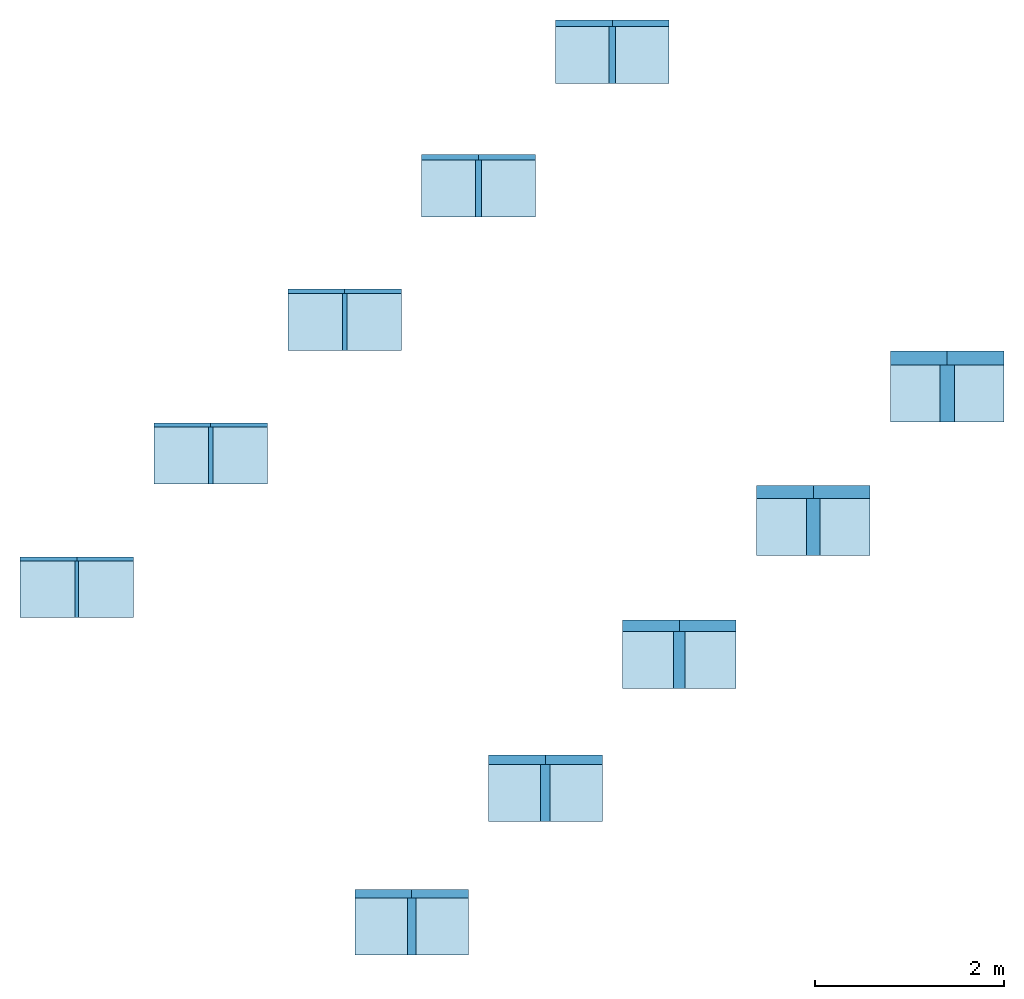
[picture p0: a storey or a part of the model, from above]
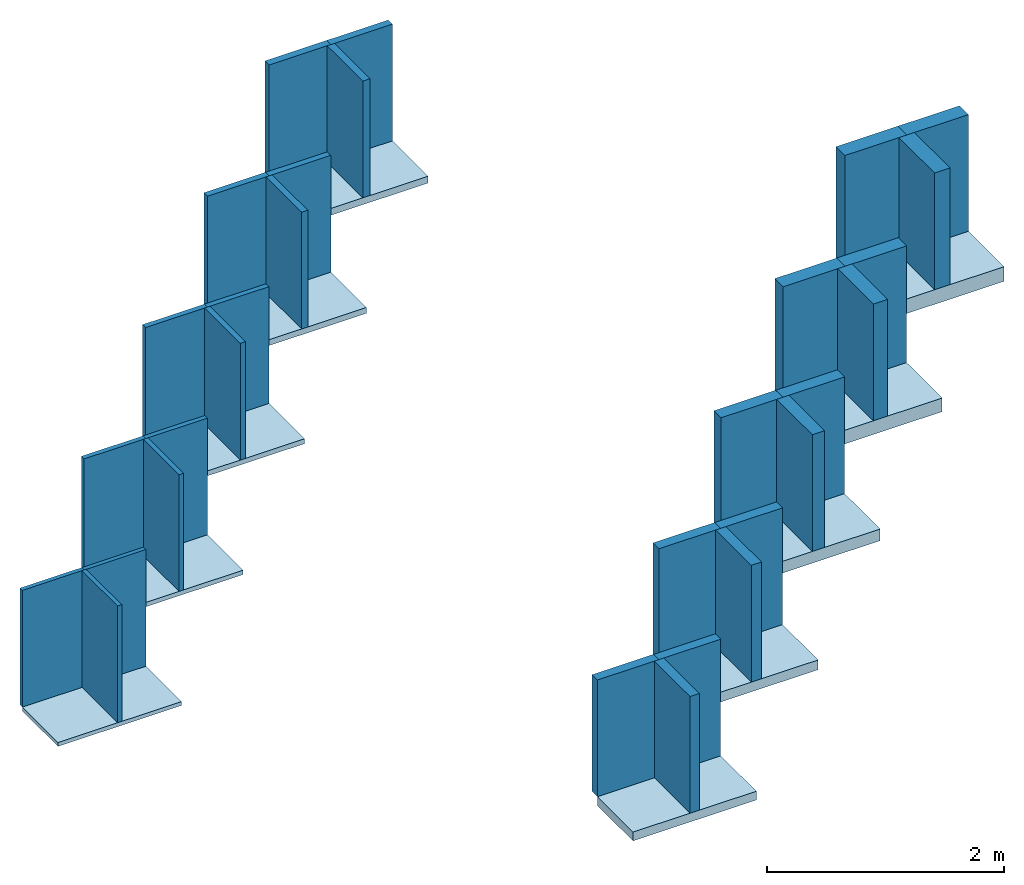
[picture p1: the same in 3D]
Properties of the parts of a building model (IFC2X3)

# File
Description: ViewDefinition [CoordinationView_V2.0, QuantityTakeOffAddOnView]
Time: 2021-05-19T20:16:55
Written by: The EXPRESS Data Manager Version 5.02.0100.07 : 28 Aug 2013
Made in: 20190108_1515(x64) - Exporter 19.1.0.0 - Alternate UI 19.1.0.0
Comment: STEP Physical File produced by: The EXPRESS Data Manager Version 5.02.0100.07 : 28 Aug 2013 * Module: EDMstepFileFactory/EDMstandAlone * Creation date: Wed May 19 20:16:55 2021 * Host: lt-026 * Database: C:\Users\WF2BF~1.POE\AppData\Local\Temp\{A69A01DA-EC1D-4794-8E67-495A6B97D631}\ifc * Database version: 5507 * Database creation date: Wed May 19 20:16:54 2021 * Schema: IFC2X3 * Model: DataRepository.ifc * Model creation date: Wed May 19 20:16:54 2021 * Header model: DataRepository.ifc_HeaderModel * Header model creation date: Wed May 19 20:16:54 2021 * EDMuser: sdai-user * EDMgroup: sdai-group * License ID and type: 5605 : Permanent license. Expiry date: * EDMstepFileFactory options: 020000

# IfcSite, Default
RefLatitude: 42, 24, 53, 508911; RefLongitude: -71, -15, -29, -58837; RefElevation: 0 mm
Other - Category: Project Information

# IfcBuilding
Pset_BuildingCommon - NumberOfStoreys: 1
Pset_ProductRequirements - Category: Project Information; sets with these values: 2

# IfcBuildingStorey: Level:Level 1, begane grond
LongName: begane grond; Elevation: 0 mm
Pset_AirSideSystemInformation - Name: begane grond
Pset_ProductRequirements - Name: begane grond; Category: Levels
Constraints - Elevation: 0 mm
Dimensions - Computation Height: 0 mm
Identity Data - Structural: no; Building Story: yes; Name: begane grond
Other - Category: Levels; Family: Level: Level 1; Family and Type: Level: Level 1; Type: Level: Level 1; Type Id: Level: Level 1
Constraints(Type) - Elevation Base: Project Base Point
Graphics(Type) - Color: 0; Line Pattern: Solid; Line Weight: 1; Symbol: NLRS_00_LAB_niveau bovenkant_gen_cadix: 1.8mm; Symbol at End 1 Default: no; Symbol at End 2 Default: yes
Identity Data(Type) - Type Name: Level 1
Other(Type) - Category: Levels; Family Name: Level

# IfcSlab: Floor:NLRS_23_FL_Mineral Wool_100x600x1200mm, Floor:NLRS_23_FL_Mineral Wool_100x600x1200mm:5011
In: begane grond
Type - PredefinedType: FLOOR; Material: Knauf Insulation_Mineral Wool 35 Ecose®minerale wol 100 mm
Type - Analytical Properties - Roughness: 1; Thermal mass: 0; Absorptance: 0.1; Heat Transfer Coefficient (U): 0.35; Thermal Resistance (R): 2.85714
Type - Construction - Function: Interior; Default Thickness: 100 mm
Type - Graphics - Coarse Scale Fill Color: 0
Type - Identity Data - Type Image: Raster image: MW 35 .jpg (2); Assembly Code: 23; Assembly Description: Vloeren; Description: Mineral Wool 35 - 100mm; Manufacturer: Knauf Insulation B.V.; Model: Mineral Wool 35 is een onbeklede minerale wolplaat met ECOSE® Technology.; Type Name: NLRS_23_FL_Mineral Wool_100x600x1200mm; URL: www.knaufinsulation.nl
Type - Other - Category: Floors; Family Name: Floor
Type - Pset_ElementShading - Roughness: 304.8 mm
Type - Pset_ManufacturerTypeInformation - Manufacturer: Knauf Insulation B.V.
Type - Pset_ProductRequirements - Category: Floors
Type - Pset_QuantityTakeOff - Reference: NLRS_23_FL_Mineral Wool_100x600x1200mm
Type - Pset_ReinforcementBarPitchOfSlab - Description: Mineral Wool 35 - 100mm; Reference: NLRS_23_FL_Mineral Wool_100x600x1200mm
Type - Pset_SlabCommon - IsExternal: no; ThermalTransmittance: 0.35 kg/K/s3; Reference: NLRS_23_FL_Mineral Wool_100x600x1200mm
Classification: 23 Vloeren (Uniformat)
Pset_SlabCommon - LoadBearing: no; PitchAngle: 0 deg
BaseQuantities - GrossArea: 0.72 m2; NetArea: 1.8 m2; GrossVolume: 72 m3; NetVolume: 0.072 m3; Perimeter: 3600 mm; Width: 100 mm
Constraints - Related to Mass: no; Room Bounding: yes; Height Offset From Level: 0 mm; Level: Level: begane grond
Dimensions - Elevation at Top: 0 mm; Area: 0.72 m2; Elevation at Bottom: -100 mm; Perimeter: 3600 mm; Thickness: 100 mm; Volume: 0.072 m3
Other - Family: Floor: NLRS_23_FL_Mineral Wool_100x600x1200mm; Family and Type: Floor: NLRS_23_FL_Mineral Wool_100x600x1200mm; Type: Floor: NLRS_23_FL_Mineral Wool_100x600x1200mm; Type Id: Floor: NLRS_23_FL_Mineral Wool_100x600x1200mm
Phasing - Phase Created: New Construction
Structural - Enable Analytical Model: no; Structural: no

# IfcSlab: Floor:NLRS_23_FL_Mineral Wool_120x600x1200mm, Floor:NLRS_23_FL_Mineral Wool_120x600x1200mm:5060
In: begane grond
Type - PredefinedType: FLOOR; Material: Knauf Insulation_Mineral Wool 35 Ecose®minerale wol 120 mm
Type - Analytical Properties - Roughness: 1; Thermal mass: 0; Absorptance: 0.1; Heat Transfer Coefficient (U): 0.291667; Thermal Resistance (R): 3.42857
Type - Construction - Function: Interior; Default Thickness: 120 mm
Type - Graphics - Coarse Scale Fill Color: 0
Type - Identity Data - Type Image: Raster image: MW 35 .jpg (2); Assembly Code: 23; Assembly Description: Vloeren; Description: Mineral Wool 35 - 120mm; Manufacturer: Knauf Insulation B.V.; Model: Mineral Wool 35 is een onbeklede minerale wolplaat met ECOSE® Technology.; Type Name: NLRS_23_FL_Mineral Wool_120x600x1200mm; URL: www.knaufinsulation.nl
Type - Other - Category: Floors; Family Name: Floor
Type - Pset_ElementShading - Roughness: 304.8 mm
Type - Pset_ManufacturerTypeInformation - Manufacturer: Knauf Insulation B.V.
Type - Pset_ProductRequirements - Category: Floors
Type - Pset_QuantityTakeOff - Reference: NLRS_23_FL_Mineral Wool_120x600x1200mm
Type - Pset_ReinforcementBarPitchOfSlab - Description: Mineral Wool 35 - 120mm; Reference: NLRS_23_FL_Mineral Wool_120x600x1200mm
Type - Pset_SlabCommon - IsExternal: no; Reference: NLRS_23_FL_Mineral Wool_120x600x1200mm; ThermalTransmittance: 0.291667 kg/K/s3
Classification: 23 Vloeren (Uniformat)
Pset_SlabCommon - LoadBearing: no; PitchAngle: 0 deg
BaseQuantities - GrossArea: 0.72 m2; NetArea: 1.872 m2; GrossVolume: 86.4 m3; NetVolume: 0.0864 m3; Perimeter: 3600 mm; Width: 120 mm
Constraints - Related to Mass: no; Room Bounding: yes; Height Offset From Level: 0 mm; Level: Level: begane grond
Dimensions - Elevation at Top: 0 mm; Area: 0.72 m2; Elevation at Bottom: -120 mm; Perimeter: 3600 mm; Thickness: 120 mm; Volume: 0.0864 m3
Other - Family: Floor: NLRS_23_FL_Mineral Wool_120x600x1200mm; Family and Type: Floor: NLRS_23_FL_Mineral Wool_120x600x1200mm; Type: Floor: NLRS_23_FL_Mineral Wool_120x600x1200mm; Type Id: Floor: NLRS_23_FL_Mineral Wool_120x600x1200mm
Phasing - Phase Created: New Construction
Structural - Enable Analytical Model: no; Structural: no

# IfcSlab: Floor:NLRS_23_FL_Mineral Wool_140x600x1200mm, Floor:NLRS_23_FL_Mineral Wool_140x600x1200mm:5083
In: begane grond
Type - PredefinedType: FLOOR; Material: Knauf Insulation_Mineral Wool 35 Ecose®minerale wol 140 mm
Type - Analytical Properties - Roughness: 1; Thermal mass: 0; Thermal Resistance (R): 4; Absorptance: 0.1; Heat Transfer Coefficient (U): 0.25
Type - Construction - Function: Interior; Default Thickness: 140 mm
Type - Graphics - Coarse Scale Fill Color: 0
Type - Identity Data - Type Image: Raster image: MW 35 .jpg (2); Assembly Code: 23; Assembly Description: Vloeren; Description: Mineral Wool 35 - 140mm; Manufacturer: Knauf Insulation B.V.; Model: Mineral Wool 35 is een onbeklede minerale wolplaat met ECOSE® Technology.; Type Name: NLRS_23_FL_Mineral Wool_140x600x1200mm; URL: www.knaufinsulation.nl
Type - Other - Category: Floors; Family Name: Floor
Type - Pset_ElementShading - Roughness: 304.8 mm
Type - Pset_ManufacturerTypeInformation - Manufacturer: Knauf Insulation B.V.
Type - Pset_ProductRequirements - Category: Floors
Type - Pset_QuantityTakeOff - Reference: NLRS_23_FL_Mineral Wool_140x600x1200mm
Type - Pset_ReinforcementBarPitchOfSlab - Description: Mineral Wool 35 - 140mm; Reference: NLRS_23_FL_Mineral Wool_140x600x1200mm
Type - Pset_SlabCommon - IsExternal: no; ThermalTransmittance: 0.25 kg/K/s3; Reference: NLRS_23_FL_Mineral Wool_140x600x1200mm
Classification: 23 Vloeren (Uniformat)
Pset_SlabCommon - LoadBearing: no; PitchAngle: 0 deg
BaseQuantities - GrossArea: 0.72 m2; NetArea: 1.944 m2; GrossVolume: 100.8 m3; NetVolume: 0.1008 m3; Perimeter: 3600 mm; Width: 140 mm
Constraints - Related to Mass: no; Room Bounding: yes; Height Offset From Level: 0 mm; Level: Level: begane grond
Dimensions - Elevation at Top: 0 mm; Area: 0.72 m2; Elevation at Bottom: -140 mm; Perimeter: 3600 mm; Thickness: 140 mm; Volume: 0.1008 m3
Other - Family: Floor: NLRS_23_FL_Mineral Wool_140x600x1200mm; Family and Type: Floor: NLRS_23_FL_Mineral Wool_140x600x1200mm; Type: Floor: NLRS_23_FL_Mineral Wool_140x600x1200mm; Type Id: Floor: NLRS_23_FL_Mineral Wool_140x600x1200mm
Phasing - Phase Created: New Construction
Structural - Enable Analytical Model: no; Structural: no

# IfcSlab: Floor:NLRS_23_FL_Mineral Wool_150x600x1200mm, Floor:NLRS_23_FL_Mineral Wool_150x600x1200mm:5092
In: begane grond
Type - PredefinedType: FLOOR; Material: Knauf Insulation_Mineral Wool 35 Ecose®minerale wol 150 mm
Type - Analytical Properties - Roughness: 1; Thermal mass: 0; Absorptance: 0.1; Heat Transfer Coefficient (U): 0.233333; Thermal Resistance (R): 4.28571
Type - Construction - Function: Interior; Default Thickness: 150 mm
Type - Graphics - Coarse Scale Fill Color: 0
Type - Identity Data - Type Image: Raster image: MW 35 .jpg (2); Assembly Code: 23; Assembly Description: Vloeren; Description: Mineral Wool 35 - 150mm; Manufacturer: Knauf Insulation B.V.; Model: Mineral Wool 35 is een onbeklede minerale wolplaat met ECOSE® Technology.; Type Name: NLRS_23_FL_Mineral Wool_150x600x1200mm; URL: www.knaufinsulation.nl
Type - Other - Category: Floors; Family Name: Floor
Type - Pset_ElementShading - Roughness: 304.8 mm
Type - Pset_ManufacturerTypeInformation - Manufacturer: Knauf Insulation B.V.
Type - Pset_ProductRequirements - Category: Floors
Type - Pset_QuantityTakeOff - Reference: NLRS_23_FL_Mineral Wool_150x600x1200mm
Type - Pset_ReinforcementBarPitchOfSlab - Description: Mineral Wool 35 - 150mm; Reference: NLRS_23_FL_Mineral Wool_150x600x1200mm
Type - Pset_SlabCommon - IsExternal: no; Reference: NLRS_23_FL_Mineral Wool_150x600x1200mm; ThermalTransmittance: 0.233333 kg/K/s3
Classification: 23 Vloeren (Uniformat)
Pset_SlabCommon - LoadBearing: no; PitchAngle: 0 deg
BaseQuantities - GrossArea: 0.72 m2; NetArea: 1.98 m2; GrossVolume: 108 m3; NetVolume: 0.108 m3; Perimeter: 3600 mm; Width: 150 mm
Constraints - Related to Mass: no; Room Bounding: yes; Height Offset From Level: 0 mm; Level: Level: begane grond
Dimensions - Elevation at Top: 0 mm; Area: 0.72 m2; Elevation at Bottom: -150 mm; Perimeter: 3600 mm; Thickness: 150 mm; Volume: 0.108 m3
Other - Family: Floor: NLRS_23_FL_Mineral Wool_150x600x1200mm; Family and Type: Floor: NLRS_23_FL_Mineral Wool_150x600x1200mm; Type: Floor: NLRS_23_FL_Mineral Wool_150x600x1200mm; Type Id: Floor: NLRS_23_FL_Mineral Wool_150x600x1200mm
Phasing - Phase Created: New Construction
Structural - Enable Analytical Model: no; Structural: no

# IfcSlab: Floor:NLRS_23_FL_Mineral Wool_40x600x1200mm, Floor:NLRS_23_FL_Mineral Wool_40x600x1200mm:4095
In: begane grond
Type - PredefinedType: FLOOR; Material: Knauf Insulation_Mineral Wool 35 Ecose®minerale wol 40 mm
Type - Analytical Properties - Roughness: 1; Thermal mass: 0; Absorptance: 0.1; Heat Transfer Coefficient (U): 0.875; Thermal Resistance (R): 1.14286
Type - Construction - Function: Interior; Default Thickness: 40 mm
Type - Graphics - Coarse Scale Fill Color: 0
Type - Identity Data - Type Image: Raster image: MW 35 .jpg (2); Assembly Code: 23; Assembly Description: Vloeren; Description: Mineral Wool 35 - 40mm; Manufacturer: Knauf Insulation B.V.; Model: Mineral Wool 35 is een onbeklede minerale wolplaat met ECOSE® Technology.; Type Name: NLRS_23_FL_Mineral Wool_40x600x1200mm; URL: www.knaufinsulation.nl
Type - Other - Category: Floors; Family Name: Floor
Type - Pset_ElementShading - Roughness: 304.8 mm
Type - Pset_ManufacturerTypeInformation - Manufacturer: Knauf Insulation B.V.
Type - Pset_ProductRequirements - Category: Floors
Type - Pset_QuantityTakeOff - Reference: NLRS_23_FL_Mineral Wool_40x600x1200mm
Type - Pset_ReinforcementBarPitchOfSlab - Description: Mineral Wool 35 - 40mm; Reference: NLRS_23_FL_Mineral Wool_40x600x1200mm
Type - Pset_SlabCommon - IsExternal: no; Reference: NLRS_23_FL_Mineral Wool_40x600x1200mm; ThermalTransmittance: 0.875 kg/K/s3
Classification: 23 Vloeren (Uniformat)
Pset_SlabCommon - LoadBearing: no; PitchAngle: 0 deg
BaseQuantities - GrossArea: 0.72 m2; NetArea: 1.584 m2; GrossVolume: 28.8 m3; NetVolume: 0.0288 m3; Perimeter: 3600 mm; Width: 40 mm
Constraints - Related to Mass: no; Room Bounding: yes; Height Offset From Level: 0 mm; Level: Level: begane grond
Dimensions - Area: 0.72 m2; Elevation at Bottom: -40 mm; Elevation at Top: 0 mm; Perimeter: 3600 mm; Thickness: 40 mm; Volume: 0.0288 m3
Other - Family: Floor: NLRS_23_FL_Mineral Wool_40x600x1200mm; Family and Type: Floor: NLRS_23_FL_Mineral Wool_40x600x1200mm; Type: Floor: NLRS_23_FL_Mineral Wool_40x600x1200mm; Type Id: Floor: NLRS_23_FL_Mineral Wool_40x600x1200mm
Phasing - Phase Created: New Construction
Structural - Enable Analytical Model: no; Structural: no

# IfcSlab: Floor:NLRS_23_FL_Mineral Wool_45x600x1200mm, Floor:NLRS_23_FL_Mineral Wool_45x600x1200mm:4236
In: begane grond
Type - PredefinedType: FLOOR; Material: Knauf Insulation_Mineral Wool 35 Ecose®minerale wol 45 mm
Type - Analytical Properties - Roughness: 1; Thermal mass: 0; Absorptance: 0.1; Heat Transfer Coefficient (U): 0.777778; Thermal Resistance (R): 1.28571
Type - Construction - Function: Interior; Default Thickness: 45 mm
Type - Graphics - Coarse Scale Fill Color: 0
Type - Identity Data - Type Image: Raster image: MW 35 .jpg (2); Assembly Code: 23; Assembly Description: Vloeren; Description: Mineral Wool 35 - 45mm; Manufacturer: Knauf Insulation B.V.; Model: Mineral Wool 35 is een onbeklede minerale wolplaat met ECOSE® Technology.; Type Name: NLRS_23_FL_Mineral Wool_45x600x1200mm; URL: www.knaufinsulation.nl
Type - Other - Category: Floors; Family Name: Floor
Type - Pset_ElementShading - Roughness: 304.8 mm
Type - Pset_ManufacturerTypeInformation - Manufacturer: Knauf Insulation B.V.
Type - Pset_ProductRequirements - Category: Floors
Type - Pset_QuantityTakeOff - Reference: NLRS_23_FL_Mineral Wool_45x600x1200mm
Type - Pset_ReinforcementBarPitchOfSlab - Description: Mineral Wool 35 - 45mm; Reference: NLRS_23_FL_Mineral Wool_45x600x1200mm
Type - Pset_SlabCommon - IsExternal: no; Reference: NLRS_23_FL_Mineral Wool_45x600x1200mm; ThermalTransmittance: 0.777778 kg/K/s3
Classification: 23 Vloeren (Uniformat)
Pset_SlabCommon - LoadBearing: no; PitchAngle: 0 deg
BaseQuantities - GrossArea: 0.72 m2; NetArea: 1.602 m2; GrossVolume: 32.4 m3; NetVolume: 0.0324 m3; Perimeter: 3600 mm; Width: 45 mm
Constraints - Related to Mass: no; Room Bounding: yes; Height Offset From Level: 0 mm; Level: Level: begane grond
Dimensions - Elevation at Top: 0 mm; Area: 0.72 m2; Elevation at Bottom: -45 mm; Perimeter: 3600 mm; Thickness: 45 mm; Volume: 0.0324 m3
Other - Family: Floor: NLRS_23_FL_Mineral Wool_45x600x1200mm; Family and Type: Floor: NLRS_23_FL_Mineral Wool_45x600x1200mm; Type: Floor: NLRS_23_FL_Mineral Wool_45x600x1200mm; Type Id: Floor: NLRS_23_FL_Mineral Wool_45x600x1200mm
Phasing - Phase Created: New Construction
Structural - Enable Analytical Model: no; Structural: no

# IfcSlab: Floor:NLRS_23_FL_Mineral Wool_50x600x1200mm, Floor:NLRS_23_FL_Mineral Wool_50x600x1200mm:4284
In: begane grond
Type - PredefinedType: FLOOR; Material: Knauf Insulation_Mineral Wool 35 Ecose®minerale wol 50 mm
Type - Analytical Properties - Roughness: 1; Thermal mass: 0; Absorptance: 0.1; Heat Transfer Coefficient (U): 0.7; Thermal Resistance (R): 1.42857
Type - Construction - Function: Interior; Default Thickness: 50 mm
Type - Graphics - Coarse Scale Fill Color: 0
Type - Identity Data - Type Image: Raster image: MW 35 .jpg (2); Assembly Code: 23; Assembly Description: Vloeren; Description: Mineral Wool 35 - 50mm; Manufacturer: Knauf Insulation B.V.; Model: Mineral Wool 35 is een onbeklede minerale wolplaat met ECOSE® Technology.; Type Name: NLRS_23_FL_Mineral Wool_50x600x1200mm; URL: www.knaufinsulation.nl
Type - Other - Category: Floors; Family Name: Floor
Type - Pset_ElementShading - Roughness: 304.8 mm
Type - Pset_ManufacturerTypeInformation - Manufacturer: Knauf Insulation B.V.
Type - Pset_ProductRequirements - Category: Floors
Type - Pset_QuantityTakeOff - Reference: NLRS_23_FL_Mineral Wool_50x600x1200mm
Type - Pset_ReinforcementBarPitchOfSlab - Description: Mineral Wool 35 - 50mm; Reference: NLRS_23_FL_Mineral Wool_50x600x1200mm
Type - Pset_SlabCommon - IsExternal: no; ThermalTransmittance: 0.7 kg/K/s3; Reference: NLRS_23_FL_Mineral Wool_50x600x1200mm
Classification: 23 Vloeren (Uniformat)
Pset_SlabCommon - LoadBearing: no; PitchAngle: 0 deg
BaseQuantities - GrossArea: 0.72 m2; NetArea: 1.62 m2; GrossVolume: 36 m3; NetVolume: 0.036 m3; Perimeter: 3600 mm; Width: 50 mm
Constraints - Related to Mass: no; Room Bounding: yes; Height Offset From Level: 0 mm; Level: Level: begane grond
Dimensions - Elevation at Top: 0 mm; Area: 0.72 m2; Elevation at Bottom: -50 mm; Perimeter: 3600 mm; Thickness: 50 mm; Volume: 0.036 m3
Other - Family: Floor: NLRS_23_FL_Mineral Wool_50x600x1200mm; Family and Type: Floor: NLRS_23_FL_Mineral Wool_50x600x1200mm; Type: Floor: NLRS_23_FL_Mineral Wool_50x600x1200mm; Type Id: Floor: NLRS_23_FL_Mineral Wool_50x600x1200mm
Phasing - Phase Created: New Construction
Structural - Enable Analytical Model: no; Structural: no

# IfcSlab: Floor:NLRS_23_FL_Mineral Wool_60x600x1200mm, Floor:NLRS_23_FL_Mineral Wool_60x600x1200mm:4293
In: begane grond
Type - PredefinedType: FLOOR; Material: Knauf Insulation_Mineral Wool 35 Ecose®minerale wol 60 mm
Type - Analytical Properties - Roughness: 1; Thermal mass: 0; Absorptance: 0.1; Heat Transfer Coefficient (U): 0.583333; Thermal Resistance (R): 1.71429
Type - Construction - Function: Interior; Default Thickness: 60 mm
Type - Graphics - Coarse Scale Fill Color: 0
Type - Identity Data - Type Image: Raster image: MW 35 .jpg (2); Assembly Code: 23; Assembly Description: Vloeren; Description: Mineral Wool 35 - 60mm; Manufacturer: Knauf Insulation B.V.; Model: Mineral Wool 35 is een onbeklede minerale wolplaat met ECOSE® Technology.; Type Name: NLRS_23_FL_Mineral Wool_60x600x1200mm; URL: www.knaufinsulation.nl
Type - Other - Category: Floors; Family Name: Floor
Type - Pset_ElementShading - Roughness: 304.8 mm
Type - Pset_ManufacturerTypeInformation - Manufacturer: Knauf Insulation B.V.
Type - Pset_ProductRequirements - Category: Floors
Type - Pset_QuantityTakeOff - Reference: NLRS_23_FL_Mineral Wool_60x600x1200mm
Type - Pset_ReinforcementBarPitchOfSlab - Description: Mineral Wool 35 - 60mm; Reference: NLRS_23_FL_Mineral Wool_60x600x1200mm
Type - Pset_SlabCommon - IsExternal: no; Reference: NLRS_23_FL_Mineral Wool_60x600x1200mm; ThermalTransmittance: 0.583333 kg/K/s3
Classification: 23 Vloeren (Uniformat)
Pset_SlabCommon - LoadBearing: no; PitchAngle: 0 deg
BaseQuantities - GrossArea: 0.72 m2; NetArea: 1.656 m2; GrossVolume: 43.2 m3; NetVolume: 0.0432 m3; Perimeter: 3600 mm; Width: 60 mm
Constraints - Related to Mass: no; Room Bounding: yes; Height Offset From Level: 0 mm; Level: Level: begane grond
Dimensions - Elevation at Top: 0 mm; Area: 0.72 m2; Elevation at Bottom: -60 mm; Perimeter: 3600 mm; Thickness: 60 mm; Volume: 0.0432 m3
Other - Family: Floor: NLRS_23_FL_Mineral Wool_60x600x1200mm; Family and Type: Floor: NLRS_23_FL_Mineral Wool_60x600x1200mm; Type: Floor: NLRS_23_FL_Mineral Wool_60x600x1200mm; Type Id: Floor: NLRS_23_FL_Mineral Wool_60x600x1200mm
Phasing - Phase Created: New Construction
Structural - Enable Analytical Model: no; Structural: no

# IfcSlab: Floor:NLRS_23_FL_Mineral Wool_70x600x1200mm, Floor:NLRS_23_FL_Mineral Wool_70x600x1200mm:4302
In: begane grond
Type - PredefinedType: FLOOR; Material: Knauf Insulation_Mineral Wool 35 Ecose®minerale wol 70 mm
Type - Analytical Properties - Roughness: 1; Thermal mass: 0; Heat Transfer Coefficient (U): 0.5; Thermal Resistance (R): 2; Absorptance: 0.1
Type - Construction - Function: Interior; Default Thickness: 70 mm
Type - Graphics - Coarse Scale Fill Color: 0
Type - Identity Data - Type Image: Raster image: MW 35 .jpg (2); Assembly Code: 23; Assembly Description: Vloeren; Description: Mineral Wool 35 - 70mm; Manufacturer: Knauf Insulation B.V.; Model: Mineral Wool 35 is een onbeklede minerale wolplaat met ECOSE® Technology.; Type Name: NLRS_23_FL_Mineral Wool_70x600x1200mm; URL: www.knaufinsulation.nl
Type - Other - Category: Floors; Family Name: Floor
Type - Pset_ElementShading - Roughness: 304.8 mm
Type - Pset_ManufacturerTypeInformation - Manufacturer: Knauf Insulation B.V.
Type - Pset_ProductRequirements - Category: Floors
Type - Pset_QuantityTakeOff - Reference: NLRS_23_FL_Mineral Wool_70x600x1200mm
Type - Pset_ReinforcementBarPitchOfSlab - Description: Mineral Wool 35 - 70mm; Reference: NLRS_23_FL_Mineral Wool_70x600x1200mm
Type - Pset_SlabCommon - IsExternal: no; ThermalTransmittance: 0.5 kg/K/s3; Reference: NLRS_23_FL_Mineral Wool_70x600x1200mm
Classification: 23 Vloeren (Uniformat)
Pset_SlabCommon - LoadBearing: no; PitchAngle: 0 deg
BaseQuantities - GrossArea: 0.72 m2; NetArea: 1.692 m2; GrossVolume: 50.4 m3; NetVolume: 0.0504 m3; Perimeter: 3600 mm; Width: 70 mm
Constraints - Related to Mass: no; Room Bounding: yes; Height Offset From Level: 0 mm; Level: Level: begane grond
Dimensions - Elevation at Top: 0 mm; Area: 0.72 m2; Elevation at Bottom: -70 mm; Perimeter: 3600 mm; Thickness: 70 mm; Volume: 0.0504 m3
Other - Family: Floor: NLRS_23_FL_Mineral Wool_70x600x1200mm; Family and Type: Floor: NLRS_23_FL_Mineral Wool_70x600x1200mm; Type: Floor: NLRS_23_FL_Mineral Wool_70x600x1200mm; Type Id: Floor: NLRS_23_FL_Mineral Wool_70x600x1200mm
Phasing - Phase Created: New Construction
Structural - Enable Analytical Model: no; Structural: no

# IfcSlab: Floor:NLRS_23_FL_Mineral Wool_90x600x1200mm, Floor:NLRS_23_FL_Mineral Wool_90x600x1200mm:4688
In: begane grond
Type - PredefinedType: FLOOR; Material: Knauf Insulation_Mineral Wool 35 Ecose®minerale wol 90 mm
Type - Analytical Properties - Roughness: 1; Thermal mass: 0; Absorptance: 0.1; Heat Transfer Coefficient (U): 0.388889; Thermal Resistance (R): 2.57143
Type - Construction - Function: Interior; Default Thickness: 90 mm
Type - Graphics - Coarse Scale Fill Color: 0
Type - Identity Data - Type Image: Raster image: MW 35 .jpg (2); Assembly Code: 23; Assembly Description: Vloeren; Description: Mineral Wool 35 - 90mm; Manufacturer: Knauf Insulation B.V.; Model: Mineral Wool 35 is een onbeklede minerale wolplaat met ECOSE® Technology.; Type Name: NLRS_23_FL_Mineral Wool_90x600x1200mm; URL: www.knaufinsulation.nl
Type - Other - Category: Floors; Family Name: Floor
Type - Pset_ElementShading - Roughness: 304.8 mm
Type - Pset_ManufacturerTypeInformation - Manufacturer: Knauf Insulation B.V.
Type - Pset_ProductRequirements - Category: Floors
Type - Pset_QuantityTakeOff - Reference: NLRS_23_FL_Mineral Wool_90x600x1200mm
Type - Pset_ReinforcementBarPitchOfSlab - Description: Mineral Wool 35 - 90mm; Reference: NLRS_23_FL_Mineral Wool_90x600x1200mm
Type - Pset_SlabCommon - IsExternal: no; Reference: NLRS_23_FL_Mineral Wool_90x600x1200mm; ThermalTransmittance: 0.388889 kg/K/s3
Classification: 23 Vloeren (Uniformat)
Pset_SlabCommon - LoadBearing: no; PitchAngle: 0 deg
BaseQuantities - GrossArea: 0.72 m2; NetArea: 1.764 m2; GrossVolume: 64.8 m3; NetVolume: 0.0648 m3; Perimeter: 3600 mm; Width: 90 mm
Constraints - Related to Mass: no; Room Bounding: yes; Height Offset From Level: 0 mm; Level: Level: begane grond
Dimensions - Elevation at Top: 0 mm; Area: 0.72 m2; Elevation at Bottom: -90 mm; Perimeter: 3600 mm; Thickness: 90 mm; Volume: 0.0648 m3
Other - Family: Floor: NLRS_23_FL_Mineral Wool_90x600x1200mm; Family and Type: Floor: NLRS_23_FL_Mineral Wool_90x600x1200mm; Type: Floor: NLRS_23_FL_Mineral Wool_90x600x1200mm; Type Id: Floor: NLRS_23_FL_Mineral Wool_90x600x1200mm
Phasing - Phase Created: New Construction
Structural - Enable Analytical Model: no; Structural: no

# IfcWallStandardCase: Basic Wall:NLRS_22_WA_Mineral Wool 35_100x600x1200mm (3)
In: begane grond
Type - PredefinedType: STANDARD; Material: Knauf Insulation_Mineral Wool 35 Ecose®minerale wol 100 mm
Type - Analytical Properties - Roughness: 1; Thermal mass: 0; Absorptance: 0.1; Heat Transfer Coefficient (U): 0.35; Thermal Resistance (R): 2.85714
Type - Construction - Function: Interior; Wrapping at Inserts: Do not wrap; Width: 100 mm
Type - Graphics - Coarse Scale Fill Color: 0
Type - Identity Data - Type Image: Raster image: MW 35 .jpg (2); Assembly Code: 22; Assembly Description: Binnenwanden; Description: Mineral Wool 35 - 100mm; Manufacturer: Knauf Insulation B.V.; Model: Mineral Wool 35 is een onbeklede minerale wolplaat met ECOSE® Technology.; Type Name: NLRS_22_WA_Mineral Wool 35_100x600x1200mm; URL: www.knaufinsulation.nl
Type - Other - Category: Walls; Family Name: Basic Wall
Type - Pset_ElementShading - Roughness: 304.8 mm
Type - Pset_ManufacturerTypeInformation - Manufacturer: Knauf Insulation B.V.
Type - Pset_ProductRequirements - Category: Walls
Type - Pset_QuantityTakeOff - Reference: NLRS_22_WA_Mineral Wool 35_100x600x1200mm
Type - Pset_ReinforcementBarPitchOfWall - Description: Mineral Wool 35 - 100mm; Reference: NLRS_22_WA_Mineral Wool 35_100x600x1200mm
Type - Pset_WallCommon - IsExternal: no; Reference: NLRS_22_WA_Mineral Wool 35_100x600x1200mm; ThermalTransmittance: 0.35 kg/K/s3
Classification: 22 Binnenwanden (Uniformat)
BaseQuantities - Height: 1200 mm; Length: 600 mm; Width: 100 mm; GrossFootprintArea: 0.06 m2; NetVolume: 72000000 m3; NetSideArea: 720000 m2
Constraints - Base Constraint: Level: begane grond; Base Extension Distance: 0 mm; Base is Attached: no; Base Offset: 0 mm; Location Line: Wall Centerline; Related to Mass: no; Room Bounding: yes; Top Constraint: Level: lengte plaat; Top Extension Distance: 0 mm; Top is Attached: no; Top Offset: 0 mm; Unconnected Height: 1200 mm
Dimensions - Area: 0.72 m2; Length: 600 mm; Volume: 0.072 m3
Other - Family: Basic Wall: NLRS_22_WA_Mineral Wool 35_100x600x1200mm; Family and Type: Basic Wall: NLRS_22_WA_Mineral Wool 35_100x600x1200mm; Type: Basic Wall: NLRS_22_WA_Mineral Wool 35_100x600x1200mm; Type Id: Basic Wall: NLRS_22_WA_Mineral Wool 35_100x600x1200mm
Phasing - Phase Created: New Construction
Structural - Enable Analytical Model: no; Structural: no; Structural Usage: Non-bearing
Pset_WallCommon - ExtendToStructure: no; LoadBearing: no
Name (Basic Wall:NLRS_22_WA_Mineral Wool 35_100x600x1200mm:...)
3868
3869
3870

# IfcWallStandardCase: Basic Wall:NLRS_22_WA_Mineral Wool 35_120x600x1200mm (3)
In: begane grond
Type - PredefinedType: STANDARD; Material: Knauf Insulation_Mineral Wool 35 Ecose®minerale wol 120 mm
Type - Analytical Properties - Roughness: 1; Thermal mass: 0; Absorptance: 0.1; Heat Transfer Coefficient (U): 0.291667; Thermal Resistance (R): 3.42857
Type - Construction - Function: Interior; Wrapping at Inserts: Do not wrap; Width: 120 mm
Type - Graphics - Coarse Scale Fill Color: 0
Type - Identity Data - Type Image: Raster image: MW 35 .jpg (2); Assembly Code: 22; Assembly Description: Binnenwanden; Description: Mineral Wool 35 - 120mm; Manufacturer: Knauf Insulation B.V.; Model: Mineral Wool 35 is een onbeklede minerale wolplaat met ECOSE® Technology.; Type Name: NLRS_22_WA_Mineral Wool 35_120x600x1200mm; URL: www.knaufinsulation.nl
Type - Other - Category: Walls; Family Name: Basic Wall
Type - Pset_ElementShading - Roughness: 304.8 mm
Type - Pset_ManufacturerTypeInformation - Manufacturer: Knauf Insulation B.V.
Type - Pset_ProductRequirements - Category: Walls
Type - Pset_QuantityTakeOff - Reference: NLRS_22_WA_Mineral Wool 35_120x600x1200mm
Type - Pset_ReinforcementBarPitchOfWall - Description: Mineral Wool 35 - 120mm; Reference: NLRS_22_WA_Mineral Wool 35_120x600x1200mm
Type - Pset_WallCommon - IsExternal: no; Reference: NLRS_22_WA_Mineral Wool 35_120x600x1200mm; ThermalTransmittance: 0.291667 kg/K/s3
Classification: 22 Binnenwanden (Uniformat)
BaseQuantities - Height: 1200 mm; Length: 600 mm; Width: 120 mm; GrossFootprintArea: 0.072 m2; NetVolume: 86400000 m3; NetSideArea: 720000 m2
Constraints - Base Constraint: Level: begane grond; Base Extension Distance: 0 mm; Base is Attached: no; Base Offset: 0 mm; Location Line: Wall Centerline; Related to Mass: no; Room Bounding: yes; Top Constraint: Level: lengte plaat; Top Extension Distance: 0 mm; Top is Attached: no; Top Offset: 0 mm; Unconnected Height: 1200 mm
Dimensions - Area: 0.72 m2; Length: 600 mm; Volume: 0.0864 m3
Other - Family: Basic Wall: NLRS_22_WA_Mineral Wool 35_120x600x1200mm; Family and Type: Basic Wall: NLRS_22_WA_Mineral Wool 35_120x600x1200mm; Type: Basic Wall: NLRS_22_WA_Mineral Wool 35_120x600x1200mm; Type Id: Basic Wall: NLRS_22_WA_Mineral Wool 35_120x600x1200mm
Phasing - Phase Created: New Construction
Structural - Enable Analytical Model: no; Structural: no; Structural Usage: Non-bearing
Pset_WallCommon - ExtendToStructure: no; LoadBearing: no
Name (Basic Wall:NLRS_22_WA_Mineral Wool 35_120x600x1200mm:...)
3871
3872
3873

# IfcWallStandardCase: Basic Wall:NLRS_22_WA_Mineral Wool 35_140x600x1200mm (3)
In: begane grond
Type - PredefinedType: STANDARD; Material: Knauf Insulation_Mineral Wool 35 Ecose®minerale wol 140 mm
Type - Analytical Properties - Roughness: 1; Thermal mass: 0; Absorptance: 0.1; Heat Transfer Coefficient (U): 0.25; Thermal Resistance (R): 4
Type - Construction - Function: Interior; Wrapping at Inserts: Do not wrap; Width: 140 mm
Type - Graphics - Coarse Scale Fill Color: 0
Type - Identity Data - Type Image: Raster image: MW 35 .jpg (2); Assembly Code: 22; Assembly Description: Binnenwanden; Description: Mineral Wool 35 - 140mm; Manufacturer: Knauf Insulation B.V.; Model: Mineral Wool 35 is een onbeklede minerale wolplaat met ECOSE® Technology.; Type Name: NLRS_22_WA_Mineral Wool 35_140x600x1200mm; URL: www.knaufinsulation.nl
Type - Other - Category: Walls; Family Name: Basic Wall
Type - Pset_ElementShading - Roughness: 304.8 mm
Type - Pset_ManufacturerTypeInformation - Manufacturer: Knauf Insulation B.V.
Type - Pset_ProductRequirements - Category: Walls
Type - Pset_QuantityTakeOff - Reference: NLRS_22_WA_Mineral Wool 35_140x600x1200mm
Type - Pset_ReinforcementBarPitchOfWall - Description: Mineral Wool 35 - 140mm; Reference: NLRS_22_WA_Mineral Wool 35_140x600x1200mm
Type - Pset_WallCommon - IsExternal: no; Reference: NLRS_22_WA_Mineral Wool 35_140x600x1200mm; ThermalTransmittance: 0.25 kg/K/s3
Classification: 22 Binnenwanden (Uniformat)
BaseQuantities - Height: 1200 mm; Length: 600 mm; Width: 140 mm; GrossFootprintArea: 0.084 m2; NetVolume: 100800000 m3; NetSideArea: 720000 m2
Constraints - Base Constraint: Level: begane grond; Base Extension Distance: 0 mm; Base is Attached: no; Base Offset: 0 mm; Location Line: Wall Centerline; Related to Mass: no; Room Bounding: yes; Top Constraint: Level: lengte plaat; Top Extension Distance: 0 mm; Top is Attached: no; Top Offset: 0 mm; Unconnected Height: 1200 mm
Dimensions - Area: 0.72 m2; Length: 600 mm; Volume: 0.1008 m3
Other - Family: Basic Wall: NLRS_22_WA_Mineral Wool 35_140x600x1200mm; Family and Type: Basic Wall: NLRS_22_WA_Mineral Wool 35_140x600x1200mm; Type: Basic Wall: NLRS_22_WA_Mineral Wool 35_140x600x1200mm; Type Id: Basic Wall: NLRS_22_WA_Mineral Wool 35_140x600x1200mm
Phasing - Phase Created: New Construction
Structural - Enable Analytical Model: no; Structural: no; Structural Usage: Non-bearing
Pset_WallCommon - ExtendToStructure: no; LoadBearing: no
Name (Basic Wall:NLRS_22_WA_Mineral Wool 35_140x600x1200mm:...)
3874
3875
3876

# IfcWallStandardCase: Basic Wall:NLRS_22_WA_Mineral Wool 35_150x600x1200mm (3)
In: begane grond
Type - PredefinedType: STANDARD; Material: Knauf Insulation_Mineral Wool 35 Ecose®minerale wol 150 mm
Type - Analytical Properties - Roughness: 1; Thermal mass: 0; Absorptance: 0.1; Heat Transfer Coefficient (U): 0.233333; Thermal Resistance (R): 4.28571
Type - Construction - Function: Interior; Wrapping at Inserts: Do not wrap; Width: 150 mm
Type - Graphics - Coarse Scale Fill Color: 0
Type - Identity Data - Type Image: Raster image: MW 35 .jpg (2); Assembly Code: 22; Assembly Description: Binnenwanden; Description: Mineral Wool 35 - 150mm; Manufacturer: Knauf Insulation B.V.; Model: Mineral Wool 35 is een onbeklede minerale wolplaat met ECOSE® Technology.; Type Name: NLRS_22_WA_Mineral Wool 35_150x600x1200mm; URL: www.knaufinsulation.nl
Type - Other - Category: Walls; Family Name: Basic Wall
Type - Pset_ElementShading - Roughness: 304.8 mm
Type - Pset_ManufacturerTypeInformation - Manufacturer: Knauf Insulation B.V.
Type - Pset_ProductRequirements - Category: Walls
Type - Pset_QuantityTakeOff - Reference: NLRS_22_WA_Mineral Wool 35_150x600x1200mm
Type - Pset_ReinforcementBarPitchOfWall - Description: Mineral Wool 35 - 150mm; Reference: NLRS_22_WA_Mineral Wool 35_150x600x1200mm
Type - Pset_WallCommon - IsExternal: no; Reference: NLRS_22_WA_Mineral Wool 35_150x600x1200mm; ThermalTransmittance: 0.233333 kg/K/s3
Classification: 22 Binnenwanden (Uniformat)
BaseQuantities - Height: 1200 mm; Length: 600 mm; Width: 150 mm; GrossFootprintArea: 0.09 m2; NetVolume: 108000000 m3; NetSideArea: 720000 m2
Constraints - Base Constraint: Level: begane grond; Base Extension Distance: 0 mm; Base is Attached: no; Base Offset: 0 mm; Location Line: Wall Centerline; Related to Mass: no; Room Bounding: yes; Top Constraint: Level: lengte plaat; Top Extension Distance: 0 mm; Top is Attached: no; Top Offset: 0 mm; Unconnected Height: 1200 mm
Dimensions - Area: 0.72 m2; Length: 600 mm; Volume: 0.108 m3
Other - Family: Basic Wall: NLRS_22_WA_Mineral Wool 35_150x600x1200mm; Family and Type: Basic Wall: NLRS_22_WA_Mineral Wool 35_150x600x1200mm; Type: Basic Wall: NLRS_22_WA_Mineral Wool 35_150x600x1200mm; Type Id: Basic Wall: NLRS_22_WA_Mineral Wool 35_150x600x1200mm
Phasing - Phase Created: New Construction
Structural - Enable Analytical Model: no; Structural: no; Structural Usage: Non-bearing
Pset_WallCommon - ExtendToStructure: no; LoadBearing: no
Name (Basic Wall:NLRS_22_WA_Mineral Wool 35_150x600x1200mm:...)
3877
3878
3879

# IfcWallStandardCase: Basic Wall:NLRS_22_WA_Mineral Wool 35_40x600x1200mm (3)
In: begane grond
Type - PredefinedType: STANDARD; Material: Knauf Insulation_Mineral Wool 35 Ecose®minerale wol 40 mm
Type - Analytical Properties - Absorptance: 0.1; Heat Transfer Coefficient (U): 0.875; Roughness: 1; Thermal mass: 0; Thermal Resistance (R): 1.14286
Type - Construction - Function: Interior; Width: 40 mm; Wrapping at Inserts: Do not wrap
Type - Graphics - Coarse Scale Fill Color: 0
Type - Identity Data - Assembly Code: 22; Assembly Description: Binnenwanden; Description: Mineral Wool 35 - 40mm; Manufacturer: Knauf Insulation B.V.; Model: Mineral Wool 35 is een onbeklede minerale wolplaat met ECOSE® Technology.; Type Image: Raster image: MW 35 .jpg (2); Type Name: NLRS_22_WA_Mineral Wool 35_40x600x1200mm; URL: www.knaufinsulation.nl
Type - Other - Category: Walls; Family Name: Basic Wall
Type - Pset_ElementShading - Roughness: 304.8 mm
Type - Pset_ManufacturerTypeInformation - Manufacturer: Knauf Insulation B.V.
Type - Pset_ProductRequirements - Category: Walls
Type - Pset_QuantityTakeOff - Reference: NLRS_22_WA_Mineral Wool 35_40x600x1200mm
Type - Pset_ReinforcementBarPitchOfWall - Description: Mineral Wool 35 - 40mm; Reference: NLRS_22_WA_Mineral Wool 35_40x600x1200mm
Type - Pset_WallCommon - Reference: NLRS_22_WA_Mineral Wool 35_40x600x1200mm; ThermalTransmittance: 0.875 kg/K/s3; IsExternal: no
Classification: 22 Binnenwanden (Uniformat)
BaseQuantities - Height: 1200 mm; Length: 600 mm; Width: 40 mm; GrossFootprintArea: 0.024 m2; NetVolume: 28800000 m3; NetSideArea: 720000 m2
Constraints - Base Constraint: Level: begane grond; Base Extension Distance: 0 mm; Base is Attached: no; Base Offset: 0 mm; Location Line: Wall Centerline; Related to Mass: no; Room Bounding: yes; Top Constraint: Level: lengte plaat; Top Extension Distance: 0 mm; Top is Attached: no; Top Offset: 0 mm; Unconnected Height: 1200 mm
Dimensions - Area: 0.72 m2; Length: 600 mm; Volume: 0.0288 m3
Other - Family: Basic Wall: NLRS_22_WA_Mineral Wool 35_40x600x1200mm; Family and Type: Basic Wall: NLRS_22_WA_Mineral Wool 35_40x600x1200mm; Type: Basic Wall: NLRS_22_WA_Mineral Wool 35_40x600x1200mm; Type Id: Basic Wall: NLRS_22_WA_Mineral Wool 35_40x600x1200mm
Phasing - Phase Created: New Construction
Structural - Enable Analytical Model: no; Structural: no; Structural Usage: Non-bearing
Pset_WallCommon - ExtendToStructure: no; LoadBearing: no
Name (Basic Wall:NLRS_22_WA_Mineral Wool 35_40x600x1200mm:...)
2458
3351
3395

# IfcWallStandardCase: Basic Wall:NLRS_22_WA_Mineral Wool 35_45x600x1200mm (3)
In: begane grond
Type - PredefinedType: STANDARD; Material: Knauf Insulation_Mineral Wool 35 Ecose®minerale wol 45 mm
Type - Analytical Properties - Roughness: 1; Thermal mass: 0; Absorptance: 0.1; Heat Transfer Coefficient (U): 0.777778; Thermal Resistance (R): 1.28571
Type - Construction - Function: Interior; Wrapping at Inserts: Do not wrap; Width: 45 mm
Type - Graphics - Coarse Scale Fill Color: 0
Type - Identity Data - Type Image: Raster image: MW 35 .jpg (2); Assembly Code: 22; Assembly Description: Binnenwanden; Description: Mineral Wool 35 - 45mm; Manufacturer: Knauf Insulation B.V.; Model: Mineral Wool 35 is een onbeklede minerale wolplaat met ECOSE® Technology.; Type Name: NLRS_22_WA_Mineral Wool 35_45x600x1200mm; URL: www.knaufinsulation.nl
Type - Other - Category: Walls; Family Name: Basic Wall
Type - Pset_ElementShading - Roughness: 304.8 mm
Type - Pset_ManufacturerTypeInformation - Manufacturer: Knauf Insulation B.V.
Type - Pset_ProductRequirements - Category: Walls
Type - Pset_QuantityTakeOff - Reference: NLRS_22_WA_Mineral Wool 35_45x600x1200mm
Type - Pset_ReinforcementBarPitchOfWall - Description: Mineral Wool 35 - 45mm; Reference: NLRS_22_WA_Mineral Wool 35_45x600x1200mm
Type - Pset_WallCommon - IsExternal: no; Reference: NLRS_22_WA_Mineral Wool 35_45x600x1200mm; ThermalTransmittance: 0.777778 kg/K/s3
Classification: 22 Binnenwanden (Uniformat)
BaseQuantities - Height: 1200 mm; Length: 600 mm; Width: 45 mm; GrossFootprintArea: 0.027 m2; NetVolume: 32400000 m3; NetSideArea: 720000 m2
Constraints - Base Constraint: Level: begane grond; Base Extension Distance: 0 mm; Base is Attached: no; Base Offset: 0 mm; Location Line: Wall Centerline; Related to Mass: no; Room Bounding: yes; Top Constraint: Level: lengte plaat; Top Extension Distance: 0 mm; Top is Attached: no; Top Offset: 0 mm; Unconnected Height: 1200 mm
Dimensions - Area: 0.72 m2; Length: 600 mm; Volume: 0.0324 m3
Other - Family: Basic Wall: NLRS_22_WA_Mineral Wool 35_45x600x1200mm; Family and Type: Basic Wall: NLRS_22_WA_Mineral Wool 35_45x600x1200mm; Type: Basic Wall: NLRS_22_WA_Mineral Wool 35_45x600x1200mm; Type Id: Basic Wall: NLRS_22_WA_Mineral Wool 35_45x600x1200mm
Phasing - Phase Created: New Construction
Structural - Enable Analytical Model: no; Structural: no; Structural Usage: Non-bearing
Pset_WallCommon - ExtendToStructure: no; LoadBearing: no
Name (Basic Wall:NLRS_22_WA_Mineral Wool 35_45x600x1200mm:...)
3514
3516
3517

# IfcWallStandardCase: Basic Wall:NLRS_22_WA_Mineral Wool 35_50x600x1200mm (3)
In: begane grond
Type - PredefinedType: STANDARD; Material: Knauf Insulation_Mineral Wool 35 Ecose®minerale wol 50 mm
Type - Analytical Properties - Roughness: 1; Thermal mass: 0; Absorptance: 0.1; Heat Transfer Coefficient (U): 0.7; Thermal Resistance (R): 1.42857
Type - Construction - Function: Interior; Wrapping at Inserts: Do not wrap; Width: 50 mm
Type - Graphics - Coarse Scale Fill Color: 0
Type - Identity Data - Type Image: Raster image: MW 35 .jpg (2); Assembly Code: 22; Assembly Description: Binnenwanden; Description: Mineral Wool 35 - 50mm; Manufacturer: Knauf Insulation B.V.; Model: Mineral Wool 35 is een onbeklede minerale wolplaat met ECOSE® Technology.; Type Name: NLRS_22_WA_Mineral Wool 35_50x600x1200mm; URL: www.knaufinsulation.nl
Type - Other - Category: Walls; Family Name: Basic Wall
Type - Pset_ElementShading - Roughness: 304.8 mm
Type - Pset_ManufacturerTypeInformation - Manufacturer: Knauf Insulation B.V.
Type - Pset_ProductRequirements - Category: Walls
Type - Pset_QuantityTakeOff - Reference: NLRS_22_WA_Mineral Wool 35_50x600x1200mm
Type - Pset_ReinforcementBarPitchOfWall - Description: Mineral Wool 35 - 50mm; Reference: NLRS_22_WA_Mineral Wool 35_50x600x1200mm
Type - Pset_WallCommon - IsExternal: no; Reference: NLRS_22_WA_Mineral Wool 35_50x600x1200mm; ThermalTransmittance: 0.7 kg/K/s3
Classification: 22 Binnenwanden (Uniformat)
BaseQuantities - Height: 1200 mm; Length: 600 mm; Width: 50 mm; GrossFootprintArea: 0.03 m2; NetVolume: 36000000 m3; NetSideArea: 720000 m2
Constraints - Base Constraint: Level: begane grond; Base Extension Distance: 0 mm; Base is Attached: no; Base Offset: 0 mm; Location Line: Wall Centerline; Related to Mass: no; Room Bounding: yes; Top Constraint: Level: lengte plaat; Top Extension Distance: 0 mm; Top is Attached: no; Top Offset: 0 mm; Unconnected Height: 1200 mm
Dimensions - Area: 0.72 m2; Length: 600 mm; Volume: 0.036 m3
Other - Family: Basic Wall: NLRS_22_WA_Mineral Wool 35_50x600x1200mm; Family and Type: Basic Wall: NLRS_22_WA_Mineral Wool 35_50x600x1200mm; Type: Basic Wall: NLRS_22_WA_Mineral Wool 35_50x600x1200mm; Type Id: Basic Wall: NLRS_22_WA_Mineral Wool 35_50x600x1200mm
Phasing - Phase Created: New Construction
Structural - Enable Analytical Model: no; Structural: no; Structural Usage: Non-bearing
Pset_WallCommon - ExtendToStructure: no; LoadBearing: no
Name (Basic Wall:NLRS_22_WA_Mineral Wool 35_50x600x1200mm:...)
3581
3582
3583

# IfcWallStandardCase: Basic Wall:NLRS_22_WA_Mineral Wool 35_60x600x1200mm (3)
In: begane grond
Type - PredefinedType: STANDARD; Material: Knauf Insulation_Mineral Wool 35 Ecose®minerale wol 60 mm
Type - Analytical Properties - Roughness: 1; Thermal mass: 0; Absorptance: 0.1; Heat Transfer Coefficient (U): 0.583333; Thermal Resistance (R): 1.71429
Type - Construction - Function: Interior; Wrapping at Inserts: Do not wrap; Width: 60 mm
Type - Graphics - Coarse Scale Fill Color: 0
Type - Identity Data - Type Image: Raster image: MW 35 .jpg (2); Assembly Code: 22; Assembly Description: Binnenwanden; Description: Mineral Wool 35 - 60mm; Manufacturer: Knauf Insulation B.V.; Model: Mineral Wool 35 is een onbeklede minerale wolplaat met ECOSE® Technology.; Type Name: NLRS_22_WA_Mineral Wool 35_60x600x1200mm; URL: www.knaufinsulation.nl
Type - Other - Category: Walls; Family Name: Basic Wall
Type - Pset_ElementShading - Roughness: 304.8 mm
Type - Pset_ManufacturerTypeInformation - Manufacturer: Knauf Insulation B.V.
Type - Pset_ProductRequirements - Category: Walls
Type - Pset_QuantityTakeOff - Reference: NLRS_22_WA_Mineral Wool 35_60x600x1200mm
Type - Pset_ReinforcementBarPitchOfWall - Description: Mineral Wool 35 - 60mm; Reference: NLRS_22_WA_Mineral Wool 35_60x600x1200mm
Type - Pset_WallCommon - IsExternal: no; Reference: NLRS_22_WA_Mineral Wool 35_60x600x1200mm; ThermalTransmittance: 0.583333 kg/K/s3
Classification: 22 Binnenwanden (Uniformat)
BaseQuantities - Height: 1200 mm; Length: 600 mm; Width: 60 mm; GrossFootprintArea: 0.036 m2; NetVolume: 43200000 m3; NetSideArea: 720000 m2
Constraints - Base Constraint: Level: begane grond; Base Extension Distance: 0 mm; Base is Attached: no; Base Offset: 0 mm; Location Line: Wall Centerline; Related to Mass: no; Room Bounding: yes; Top Constraint: Level: lengte plaat; Top Extension Distance: 0 mm; Top is Attached: no; Top Offset: 0 mm; Unconnected Height: 1200 mm
Dimensions - Area: 0.72 m2; Length: 600 mm; Volume: 0.0432 m3
Other - Family: Basic Wall: NLRS_22_WA_Mineral Wool 35_60x600x1200mm; Family and Type: Basic Wall: NLRS_22_WA_Mineral Wool 35_60x600x1200mm; Type: Basic Wall: NLRS_22_WA_Mineral Wool 35_60x600x1200mm; Type Id: Basic Wall: NLRS_22_WA_Mineral Wool 35_60x600x1200mm
Phasing - Phase Created: New Construction
Structural - Enable Analytical Model: no; Structural: no; Structural Usage: Non-bearing
Pset_WallCommon - ExtendToStructure: no; LoadBearing: no
Name (Basic Wall:NLRS_22_WA_Mineral Wool 35_60x600x1200mm:...)
3682
3683
3684

# IfcWallStandardCase: Basic Wall:NLRS_22_WA_Mineral Wool 35_70x600x1200mm (3)
In: begane grond
Type - PredefinedType: STANDARD; Material: Knauf Insulation_Mineral Wool 35 Ecose®minerale wol 70 mm
Type - Analytical Properties - Roughness: 1; Thermal mass: 0; Absorptance: 0.1; Heat Transfer Coefficient (U): 0.5; Thermal Resistance (R): 2
Type - Construction - Function: Interior; Wrapping at Inserts: Do not wrap; Width: 70 mm
Type - Graphics - Coarse Scale Fill Color: 0
Type - Identity Data - Type Image: Raster image: MW 35 .jpg (2); Assembly Code: 22; Assembly Description: Binnenwanden; Description: Mineral Wool 35 - 70mm; Manufacturer: Knauf Insulation B.V.; Model: Mineral Wool 35 is een onbeklede minerale wolplaat met ECOSE® Technology.; Type Name: NLRS_22_WA_Mineral Wool 35_70x600x1200mm; URL: www.knaufinsulation.nl
Type - Other - Category: Walls; Family Name: Basic Wall
Type - Pset_ElementShading - Roughness: 304.8 mm
Type - Pset_ManufacturerTypeInformation - Manufacturer: Knauf Insulation B.V.
Type - Pset_ProductRequirements - Category: Walls
Type - Pset_QuantityTakeOff - Reference: NLRS_22_WA_Mineral Wool 35_70x600x1200mm
Type - Pset_ReinforcementBarPitchOfWall - Description: Mineral Wool 35 - 70mm; Reference: NLRS_22_WA_Mineral Wool 35_70x600x1200mm
Type - Pset_WallCommon - IsExternal: no; Reference: NLRS_22_WA_Mineral Wool 35_70x600x1200mm; ThermalTransmittance: 0.5 kg/K/s3
Classification: 22 Binnenwanden (Uniformat)
BaseQuantities - Height: 1200 mm; Length: 600 mm; Width: 70 mm; GrossFootprintArea: 0.042 m2; NetVolume: 50400000 m3; NetSideArea: 720000 m2
Constraints - Base Constraint: Level: begane grond; Base Extension Distance: 0 mm; Base is Attached: no; Base Offset: 0 mm; Location Line: Wall Centerline; Related to Mass: no; Room Bounding: yes; Top Constraint: Level: lengte plaat; Top Extension Distance: 0 mm; Top is Attached: no; Top Offset: 0 mm; Unconnected Height: 1200 mm
Dimensions - Area: 0.72 m2; Length: 600 mm; Volume: 0.0504 m3
Other - Family: Basic Wall: NLRS_22_WA_Mineral Wool 35_70x600x1200mm; Family and Type: Basic Wall: NLRS_22_WA_Mineral Wool 35_70x600x1200mm; Type: Basic Wall: NLRS_22_WA_Mineral Wool 35_70x600x1200mm; Type Id: Basic Wall: NLRS_22_WA_Mineral Wool 35_70x600x1200mm
Phasing - Phase Created: New Construction
Structural - Enable Analytical Model: no; Structural: no; Structural Usage: Non-bearing
Pset_WallCommon - ExtendToStructure: no; LoadBearing: no
Name (Basic Wall:NLRS_22_WA_Mineral Wool 35_70x600x1200mm:...)
3760
3761
3762

# IfcWallStandardCase: Basic Wall:NLRS_22_WA_Mineral Wool 35_90x600x1200mm (3)
In: begane grond
Type - PredefinedType: STANDARD; Material: Knauf Insulation_Mineral Wool 35 Ecose®minerale wol 90 mm
Type - Analytical Properties - Roughness: 1; Thermal mass: 0; Absorptance: 0.1; Heat Transfer Coefficient (U): 0.388889; Thermal Resistance (R): 2.57143
Type - Construction - Function: Interior; Wrapping at Inserts: Do not wrap; Width: 90 mm
Type - Graphics - Coarse Scale Fill Color: 0
Type - Identity Data - Type Image: Raster image: MW 35 .jpg (2); Assembly Code: 22; Assembly Description: Binnenwanden; Description: Mineral Wool 35 - 90mm; Manufacturer: Knauf Insulation B.V.; Model: Mineral Wool 35 is een onbeklede minerale wolplaat met ECOSE® Technology.; Type Name: NLRS_22_WA_Mineral Wool 35_90x600x1200mm; URL: www.knaufinsulation.nl
Type - Other - Category: Walls; Family Name: Basic Wall
Type - Pset_ElementShading - Roughness: 304.8 mm
Type - Pset_ManufacturerTypeInformation - Manufacturer: Knauf Insulation B.V.
Type - Pset_ProductRequirements - Category: Walls
Type - Pset_QuantityTakeOff - Reference: NLRS_22_WA_Mineral Wool 35_90x600x1200mm
Type - Pset_ReinforcementBarPitchOfWall - Description: Mineral Wool 35 - 90mm; Reference: NLRS_22_WA_Mineral Wool 35_90x600x1200mm
Type - Pset_WallCommon - IsExternal: no; Reference: NLRS_22_WA_Mineral Wool 35_90x600x1200mm; ThermalTransmittance: 0.388889 kg/K/s3
Classification: 22 Binnenwanden (Uniformat)
BaseQuantities - Height: 1200 mm; Length: 600 mm; Width: 90 mm; GrossFootprintArea: 0.054 m2; NetVolume: 64800000 m3; NetSideArea: 720000 m2
Constraints - Base Constraint: Level: begane grond; Base Extension Distance: 0 mm; Base is Attached: no; Base Offset: 0 mm; Location Line: Wall Centerline; Related to Mass: no; Room Bounding: yes; Top Constraint: Level: lengte plaat; Top Extension Distance: 0 mm; Top is Attached: no; Top Offset: 0 mm; Unconnected Height: 1200 mm
Dimensions - Area: 0.72 m2; Length: 600 mm; Volume: 0.0648 m3
Other - Family: Basic Wall: NLRS_22_WA_Mineral Wool 35_90x600x1200mm; Family and Type: Basic Wall: NLRS_22_WA_Mineral Wool 35_90x600x1200mm; Type: Basic Wall: NLRS_22_WA_Mineral Wool 35_90x600x1200mm; Type Id: Basic Wall: NLRS_22_WA_Mineral Wool 35_90x600x1200mm
Phasing - Phase Created: New Construction
Structural - Enable Analytical Model: no; Structural: no; Structural Usage: Non-bearing
Pset_WallCommon - ExtendToStructure: no; LoadBearing: no
Name (Basic Wall:NLRS_22_WA_Mineral Wool 35_90x600x1200mm:...)
3864
3866
3867
